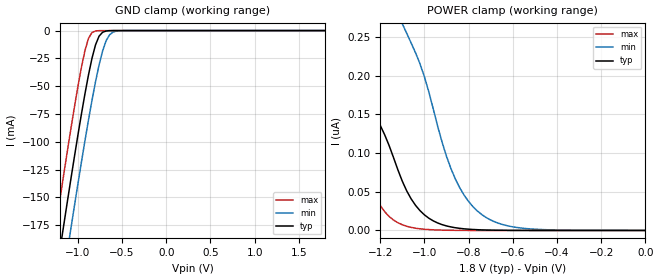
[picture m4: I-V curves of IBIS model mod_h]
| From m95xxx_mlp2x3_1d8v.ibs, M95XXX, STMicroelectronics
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|   Model mod_h
[Model]   mod_h
Model_type Input
Vinl   =   0.45V
Vinh   =   1.35V
C_comp   2.119pF   2.023pF   2.433pF
[Temperature Range]   25.0000   85.0000   -40.0000
[Voltage Range]   1.8000V   1.7000V   1.9000V
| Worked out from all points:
|   GND clamp passes 1 mA (typ) near -0.70 V on its own axis
[GND_clamp]
|Voltage   I(typ)   I(min)   I(max)
-1.8V     -520.5mA   -564.7mA   -476.1mA
-1.28V    -238.3mA   -283.2mA   -192.7mA
-1.24V    -217.2mA   -262.1mA   -171.5mA
-1.16V    -175.3mA   -220.1mA   -129.7mA
-1.08V    -134.2mA   -178.7mA   -89.03mA
-920mV    -57.12mA   -99.32mA   -18.15mA
-840mV    -24.96mA   -62.76mA   -1.769mA
-800mV    -12.85mA   -46.02mA   -321.2uA
-720mV    -1.515mA   -18.31mA   -8.596uA
-680mV    -390.8uA   -9.065mA   -1.39uA
-600mV    -23.11uA   -1.27mA    -36.27nA
1.8V      3.691pA    37.05pA    3.633pA
[POWER_clamp]
|Voltage   I(typ)   I(min)   I(max)
-1.8V     565.1nA    840.7nA    411.3nA
-1.62V    407.4nA    666nA      264nA
-1.42V    260.9nA    493.2nA    139.2nA
-1.2V     135.9nA    330.9nA    32.42nA
-1.12V    78.4nA     279.4nA    10.06nA
-1.08V    51.18nA    254.7nA    5.473nA
-980mV    15.89nA    179nA      1.172nA
-920mV    7.585nA    114.1nA    473.7pA
-860mV    3.567nA    66.57nA    203.2pA
-740mV    785.4pA    20.47nA    58.13pA
-540mV    85.55pA    2.502nA    34.76pA
0V        25.78pA    115.2pA    26.81pA
